VERSION 5.7 ;
  NOWIREEXTENSIONATPIN ON ;
  DIVIDERCHAR "/" ;
  BUSBITCHARS "[]" ;
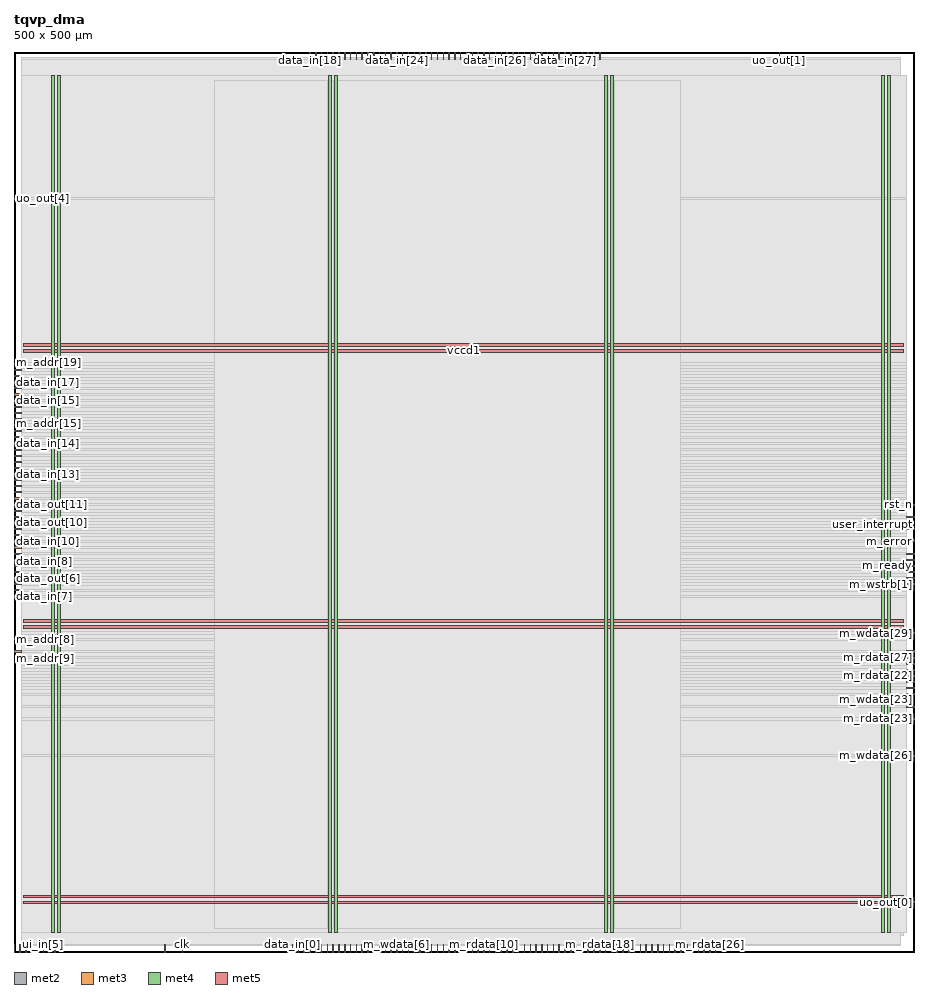
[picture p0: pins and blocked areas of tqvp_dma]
MACRO tqvp_dma
  CLASS BLOCK ;
  FOREIGN tqvp_dma ;
  ORIGIN 0.000 0.000 ;
  SIZE 500.000 BY 500.000 ;
  PIN address[0]
    DIRECTION INPUT ;
    USE SIGNAL ;
    ANTENNAGATEAREA 0.159000 ;
    PORT
      LAYER met2 ;
        RECT 248.030 496.000 248.310 500.000 ;
    END
  END address[0]
  PIN address[1]
    DIRECTION INPUT ;
    USE SIGNAL ;
    ANTENNAGATEAREA 0.159000 ;
    PORT
      LAYER met2 ;
        RECT 309.210 496.000 309.490 500.000 ;
    END
  END address[1]
  PIN address[2]
    DIRECTION INPUT ;
    USE SIGNAL ;
    ANTENNAGATEAREA 0.213000 ;
    PORT
      LAYER met2 ;
        RECT 251.250 496.000 251.530 500.000 ;
    END
  END address[2]
  PIN address[3]
    DIRECTION INPUT ;
    USE SIGNAL ;
    ANTENNAGATEAREA 0.213000 ;
    PORT
      LAYER met2 ;
        RECT 254.470 496.000 254.750 500.000 ;
    END
  END address[3]
  PIN address[4]
    DIRECTION INPUT ;
    USE SIGNAL ;
    ANTENNAGATEAREA 0.213000 ;
    PORT
      LAYER met2 ;
        RECT 257.690 496.000 257.970 500.000 ;
    END
  END address[4]
  PIN address[5]
    DIRECTION INPUT ;
    USE SIGNAL ;
    ANTENNAGATEAREA 0.159000 ;
    PORT
      LAYER met2 ;
        RECT 289.890 496.000 290.170 500.000 ;
    END
  END address[5]
  PIN clk
    DIRECTION INPUT ;
    USE SIGNAL ;
    ANTENNAGATEAREA 0.852000 ;
    ANTENNADIFFAREA 0.434700 ;
    PORT
      LAYER met2 ;
        RECT 93.470 0.000 93.750 4.000 ;
    END
  END clk
  PIN data_in[0]
    DIRECTION INPUT ;
    USE SIGNAL ;
    ANTENNAGATEAREA 0.213000 ;
    PORT
      LAYER met2 ;
        RECT 154.650 0.000 154.930 4.000 ;
    END
  END data_in[0]
  PIN data_in[10]
    DIRECTION INPUT ;
    USE SIGNAL ;
    ANTENNAGATEAREA 0.159000 ;
    PORT
      LAYER met3 ;
        RECT 0.000 227.840 4.000 228.440 ;
    END
  END data_in[10]
  PIN data_in[11]
    DIRECTION INPUT ;
    USE SIGNAL ;
    ANTENNAGATEAREA 0.159000 ;
    PORT
      LAYER met3 ;
        RECT 0.000 234.640 4.000 235.240 ;
    END
  END data_in[11]
  PIN data_in[12]
    DIRECTION INPUT ;
    USE SIGNAL ;
    ANTENNAGATEAREA 0.159000 ;
    PORT
      LAYER met3 ;
        RECT 0.000 261.840 4.000 262.440 ;
    END
  END data_in[12]
  PIN data_in[13]
    DIRECTION INPUT ;
    USE SIGNAL ;
    ANTENNAGATEAREA 0.159000 ;
    PORT
      LAYER met3 ;
        RECT 0.000 265.240 4.000 265.840 ;
    END
  END data_in[13]
  PIN data_in[14]
    DIRECTION INPUT ;
    USE SIGNAL ;
    ANTENNAGATEAREA 0.159000 ;
    PORT
      LAYER met3 ;
        RECT 0.000 282.240 4.000 282.840 ;
    END
  END data_in[14]
  PIN data_in[15]
    DIRECTION INPUT ;
    USE SIGNAL ;
    ANTENNAGATEAREA 0.159000 ;
    PORT
      LAYER met3 ;
        RECT 0.000 306.040 4.000 306.640 ;
    END
  END data_in[15]
  PIN data_in[16]
    DIRECTION INPUT ;
    USE SIGNAL ;
    ANTENNAGATEAREA 0.159000 ;
    PORT
      LAYER met3 ;
        RECT 0.000 319.640 4.000 320.240 ;
    END
  END data_in[16]
  PIN data_in[17]
    DIRECTION INPUT ;
    USE SIGNAL ;
    ANTENNAGATEAREA 0.159000 ;
    PORT
      LAYER met3 ;
        RECT 0.000 316.240 4.000 316.840 ;
    END
  END data_in[17]
  PIN data_in[18]
    DIRECTION INPUT ;
    USE SIGNAL ;
    ANTENNAGATEAREA 0.159000 ;
    PORT
      LAYER met2 ;
        RECT 164.310 496.000 164.590 500.000 ;
    END
  END data_in[18]
  PIN data_in[19]
    DIRECTION INPUT ;
    USE SIGNAL ;
    ANTENNAGATEAREA 0.159000 ;
    PORT
      LAYER met2 ;
        RECT 167.530 496.000 167.810 500.000 ;
    END
  END data_in[19]
  PIN data_in[1]
    DIRECTION INPUT ;
    USE SIGNAL ;
    ANTENNAGATEAREA 0.213000 ;
    PORT
      LAYER met2 ;
        RECT 219.050 0.000 219.330 4.000 ;
    END
  END data_in[1]
  PIN data_in[20]
    DIRECTION INPUT ;
    USE SIGNAL ;
    ANTENNAGATEAREA 0.159000 ;
    PORT
      LAYER met2 ;
        RECT 173.970 496.000 174.250 500.000 ;
    END
  END data_in[20]
  PIN data_in[21]
    DIRECTION INPUT ;
    USE SIGNAL ;
    ANTENNAGATEAREA 0.213000 ;
    PORT
      LAYER met2 ;
        RECT 170.750 496.000 171.030 500.000 ;
    END
  END data_in[21]
  PIN data_in[22]
    DIRECTION INPUT ;
    USE SIGNAL ;
    ANTENNAGATEAREA 0.159000 ;
    PORT
      LAYER met2 ;
        RECT 196.510 496.000 196.790 500.000 ;
    END
  END data_in[22]
  PIN data_in[23]
    DIRECTION INPUT ;
    USE SIGNAL ;
    ANTENNAGATEAREA 0.213000 ;
    PORT
      LAYER met2 ;
        RECT 202.950 496.000 203.230 500.000 ;
    END
  END data_in[23]
  PIN data_in[24]
    DIRECTION INPUT ;
    USE SIGNAL ;
    ANTENNAGATEAREA 0.159000 ;
    PORT
      LAYER met2 ;
        RECT 212.610 496.000 212.890 500.000 ;
    END
  END data_in[24]
  PIN data_in[25]
    DIRECTION INPUT ;
    USE SIGNAL ;
    ANTENNAGATEAREA 0.213000 ;
    PORT
      LAYER met2 ;
        RECT 222.270 496.000 222.550 500.000 ;
    END
  END data_in[25]
  PIN data_in[26]
    DIRECTION INPUT ;
    USE SIGNAL ;
    ANTENNAGATEAREA 0.213000 ;
    PORT
      LAYER met2 ;
        RECT 267.350 496.000 267.630 500.000 ;
    END
  END data_in[26]
  PIN data_in[27]
    DIRECTION INPUT ;
    USE SIGNAL ;
    ANTENNAGATEAREA 0.159000 ;
    PORT
      LAYER met2 ;
        RECT 305.990 496.000 306.270 500.000 ;
    END
  END data_in[27]
  PIN data_in[28]
    DIRECTION INPUT ;
    USE SIGNAL ;
    ANTENNAGATEAREA 0.159000 ;
    PORT
      LAYER met2 ;
        RECT 302.770 496.000 303.050 500.000 ;
    END
  END data_in[28]
  PIN data_in[29]
    DIRECTION INPUT ;
    USE SIGNAL ;
    ANTENNAGATEAREA 0.159000 ;
    PORT
      LAYER met2 ;
        RECT 299.550 496.000 299.830 500.000 ;
    END
  END data_in[29]
  PIN data_in[2]
    DIRECTION INPUT ;
    USE SIGNAL ;
    ANTENNAGATEAREA 0.213000 ;
    PORT
      LAYER met2 ;
        RECT 183.630 0.000 183.910 4.000 ;
    END
  END data_in[2]
  PIN data_in[30]
    DIRECTION INPUT ;
    USE SIGNAL ;
    ANTENNAGATEAREA 0.159000 ;
    PORT
      LAYER met2 ;
        RECT 296.330 496.000 296.610 500.000 ;
    END
  END data_in[30]
  PIN data_in[31]
    DIRECTION INPUT ;
    USE SIGNAL ;
    ANTENNAGATEAREA 0.159000 ;
    PORT
      LAYER met2 ;
        RECT 293.110 496.000 293.390 500.000 ;
    END
  END data_in[31]
  PIN data_in[3]
    DIRECTION INPUT ;
    USE SIGNAL ;
    ANTENNAGATEAREA 0.159000 ;
    PORT
      LAYER met2 ;
        RECT 202.950 0.000 203.230 4.000 ;
    END
  END data_in[3]
  PIN data_in[4]
    DIRECTION INPUT ;
    USE SIGNAL ;
    ANTENNAGATEAREA 0.213000 ;
    PORT
      LAYER met2 ;
        RECT 193.290 0.000 193.570 4.000 ;
    END
  END data_in[4]
  PIN data_in[5]
    DIRECTION INPUT ;
    USE SIGNAL ;
    ANTENNAGATEAREA 0.213000 ;
    PORT
      LAYER met2 ;
        RECT 170.750 0.000 171.030 4.000 ;
    END
  END data_in[5]
  PIN data_in[6]
    DIRECTION INPUT ;
    USE SIGNAL ;
    ANTENNAGATEAREA 0.159000 ;
    PORT
      LAYER met3 ;
        RECT 0.000 200.640 4.000 201.240 ;
    END
  END data_in[6]
  PIN data_in[7]
    DIRECTION INPUT ;
    USE SIGNAL ;
    ANTENNAGATEAREA 0.159000 ;
    PORT
      LAYER met3 ;
        RECT 0.000 197.240 4.000 197.840 ;
    END
  END data_in[7]
  PIN data_in[8]
    DIRECTION INPUT ;
    USE SIGNAL ;
    ANTENNAGATEAREA 0.159000 ;
    PORT
      LAYER met3 ;
        RECT 0.000 221.040 4.000 221.640 ;
    END
  END data_in[8]
  PIN data_in[9]
    DIRECTION INPUT ;
    USE SIGNAL ;
    ANTENNAGATEAREA 0.159000 ;
    PORT
      LAYER met3 ;
        RECT 0.000 224.440 4.000 225.040 ;
    END
  END data_in[9]
  PIN data_out[0]
    DIRECTION OUTPUT ;
    USE SIGNAL ;
    ANTENNADIFFAREA 0.445500 ;
    PORT
      LAYER met3 ;
        RECT 496.000 234.640 500.000 235.240 ;
    END
  END data_out[0]
  PIN data_out[10]
    DIRECTION OUTPUT ;
    USE SIGNAL ;
    ANTENNADIFFAREA 0.445500 ;
    PORT
      LAYER met3 ;
        RECT 0.000 238.040 4.000 238.640 ;
    END
  END data_out[10]
  PIN data_out[11]
    DIRECTION OUTPUT ;
    USE SIGNAL ;
    ANTENNADIFFAREA 0.445500 ;
    PORT
      LAYER met3 ;
        RECT 0.000 248.240 4.000 248.840 ;
    END
  END data_out[11]
  PIN data_out[12]
    DIRECTION OUTPUT ;
    USE SIGNAL ;
    ANTENNADIFFAREA 0.445500 ;
    PORT
      LAYER met3 ;
        RECT 0.000 255.040 4.000 255.640 ;
    END
  END data_out[12]
  PIN data_out[13]
    DIRECTION OUTPUT ;
    USE SIGNAL ;
    ANTENNADIFFAREA 0.445500 ;
    PORT
      LAYER met3 ;
        RECT 0.000 272.040 4.000 272.640 ;
    END
  END data_out[13]
  PIN data_out[14]
    DIRECTION OUTPUT ;
    USE SIGNAL ;
    ANTENNADIFFAREA 0.445500 ;
    PORT
      LAYER met3 ;
        RECT 0.000 275.440 4.000 276.040 ;
    END
  END data_out[14]
  PIN data_out[15]
    DIRECTION OUTPUT ;
    USE SIGNAL ;
    ANTENNADIFFAREA 0.445500 ;
    PORT
      LAYER met3 ;
        RECT 0.000 285.640 4.000 286.240 ;
    END
  END data_out[15]
  PIN data_out[16]
    DIRECTION OUTPUT ;
    USE SIGNAL ;
    ANTENNADIFFAREA 0.445500 ;
    PORT
      LAYER met3 ;
        RECT 0.000 292.440 4.000 293.040 ;
    END
  END data_out[16]
  PIN data_out[17]
    DIRECTION OUTPUT ;
    USE SIGNAL ;
    ANTENNADIFFAREA 0.445500 ;
    PORT
      LAYER met3 ;
        RECT 0.000 302.640 4.000 303.240 ;
    END
  END data_out[17]
  PIN data_out[18]
    DIRECTION OUTPUT ;
    USE SIGNAL ;
    ANTENNADIFFAREA 0.445500 ;
    PORT
      LAYER met3 ;
        RECT 0.000 312.840 4.000 313.440 ;
    END
  END data_out[18]
  PIN data_out[19]
    DIRECTION OUTPUT ;
    USE SIGNAL ;
    ANTENNADIFFAREA 0.445500 ;
    PORT
      LAYER met3 ;
        RECT 0.000 309.440 4.000 310.040 ;
    END
  END data_out[19]
  PIN data_out[1]
    DIRECTION OUTPUT ;
    USE SIGNAL ;
    ANTENNADIFFAREA 0.445500 ;
    PORT
      LAYER met2 ;
        RECT 167.530 0.000 167.810 4.000 ;
    END
  END data_out[1]
  PIN data_out[20]
    DIRECTION OUTPUT ;
    USE SIGNAL ;
    ANTENNADIFFAREA 0.795200 ;
    PORT
      LAYER met2 ;
        RECT 190.070 496.000 190.350 500.000 ;
    END
  END data_out[20]
  PIN data_out[21]
    DIRECTION OUTPUT ;
    USE SIGNAL ;
    ANTENNADIFFAREA 0.795200 ;
    PORT
      LAYER met2 ;
        RECT 193.290 496.000 193.570 500.000 ;
    END
  END data_out[21]
  PIN data_out[22]
    DIRECTION OUTPUT ;
    USE SIGNAL ;
    ANTENNADIFFAREA 0.795200 ;
    PORT
      LAYER met2 ;
        RECT 215.830 496.000 216.110 500.000 ;
    END
  END data_out[22]
  PIN data_out[23]
    DIRECTION OUTPUT ;
    USE SIGNAL ;
    ANTENNADIFFAREA 0.795200 ;
    PORT
      LAYER met2 ;
        RECT 219.050 496.000 219.330 500.000 ;
    END
  END data_out[23]
  PIN data_out[24]
    DIRECTION OUTPUT ;
    USE SIGNAL ;
    ANTENNADIFFAREA 0.795200 ;
    PORT
      LAYER met2 ;
        RECT 225.490 496.000 225.770 500.000 ;
    END
  END data_out[24]
  PIN data_out[25]
    DIRECTION OUTPUT ;
    USE SIGNAL ;
    ANTENNADIFFAREA 0.795200 ;
    PORT
      LAYER met2 ;
        RECT 209.390 496.000 209.670 500.000 ;
    END
  END data_out[25]
  PIN data_out[26]
    DIRECTION OUTPUT ;
    USE SIGNAL ;
    ANTENNADIFFAREA 0.795200 ;
    PORT
      LAYER met2 ;
        RECT 270.570 496.000 270.850 500.000 ;
    END
  END data_out[26]
  PIN data_out[27]
    DIRECTION OUTPUT ;
    USE SIGNAL ;
    ANTENNADIFFAREA 0.795200 ;
    PORT
      LAYER met2 ;
        RECT 273.790 496.000 274.070 500.000 ;
    END
  END data_out[27]
  PIN data_out[28]
    DIRECTION OUTPUT ;
    USE SIGNAL ;
    ANTENNADIFFAREA 0.795200 ;
    PORT
      LAYER met2 ;
        RECT 280.230 496.000 280.510 500.000 ;
    END
  END data_out[28]
  PIN data_out[29]
    DIRECTION OUTPUT ;
    USE SIGNAL ;
    ANTENNADIFFAREA 0.795200 ;
    PORT
      LAYER met2 ;
        RECT 260.910 496.000 261.190 500.000 ;
    END
  END data_out[29]
  PIN data_out[2]
    DIRECTION OUTPUT ;
    USE SIGNAL ;
    ANTENNADIFFAREA 0.445500 ;
    PORT
      LAYER met2 ;
        RECT 251.250 0.000 251.530 4.000 ;
    END
  END data_out[2]
  PIN data_out[30]
    DIRECTION OUTPUT ;
    USE SIGNAL ;
    ANTENNADIFFAREA 0.795200 ;
    PORT
      LAYER met2 ;
        RECT 286.670 496.000 286.950 500.000 ;
    END
  END data_out[30]
  PIN data_out[31]
    DIRECTION OUTPUT ;
    USE SIGNAL ;
    ANTENNADIFFAREA 0.795200 ;
    PORT
      LAYER met2 ;
        RECT 264.130 496.000 264.410 500.000 ;
    END
  END data_out[31]
  PIN data_out[3]
    DIRECTION OUTPUT ;
    USE SIGNAL ;
    ANTENNADIFFAREA 0.445500 ;
    PORT
      LAYER met2 ;
        RECT 186.850 0.000 187.130 4.000 ;
    END
  END data_out[3]
  PIN data_out[4]
    DIRECTION OUTPUT ;
    USE SIGNAL ;
    ANTENNADIFFAREA 0.445500 ;
    PORT
      LAYER met2 ;
        RECT 248.030 0.000 248.310 4.000 ;
    END
  END data_out[4]
  PIN data_out[5]
    DIRECTION OUTPUT ;
    USE SIGNAL ;
    ANTENNADIFFAREA 0.445500 ;
    PORT
      LAYER met3 ;
        RECT 0.000 214.240 4.000 214.840 ;
    END
  END data_out[5]
  PIN data_out[6]
    DIRECTION OUTPUT ;
    USE SIGNAL ;
    ANTENNADIFFAREA 0.445500 ;
    PORT
      LAYER met3 ;
        RECT 0.000 207.440 4.000 208.040 ;
    END
  END data_out[6]
  PIN data_out[7]
    DIRECTION OUTPUT ;
    USE SIGNAL ;
    ANTENNADIFFAREA 0.445500 ;
    PORT
      LAYER met3 ;
        RECT 0.000 210.840 4.000 211.440 ;
    END
  END data_out[7]
  PIN data_out[8]
    DIRECTION OUTPUT ;
    USE SIGNAL ;
    ANTENNADIFFAREA 0.445500 ;
    PORT
      LAYER met3 ;
        RECT 0.000 217.640 4.000 218.240 ;
    END
  END data_out[8]
  PIN data_out[9]
    DIRECTION OUTPUT ;
    USE SIGNAL ;
    ANTENNADIFFAREA 0.445500 ;
    PORT
      LAYER met3 ;
        RECT 0.000 231.240 4.000 231.840 ;
    END
  END data_out[9]
  PIN data_read_n[0]
    DIRECTION INPUT ;
    USE SIGNAL ;
    ANTENNAGATEAREA 0.213000 ;
    PORT
      LAYER met2 ;
        RECT 244.810 496.000 245.090 500.000 ;
    END
  END data_read_n[0]
  PIN data_read_n[1]
    DIRECTION INPUT ;
    USE SIGNAL ;
    ANTENNAGATEAREA 0.213000 ;
    PORT
      LAYER met2 ;
        RECT 241.590 496.000 241.870 500.000 ;
    END
  END data_read_n[1]
  PIN data_ready
    DIRECTION OUTPUT ;
    USE SIGNAL ;
    ANTENNADIFFAREA 0.445500 ;
    PORT
      LAYER met3 ;
        RECT 0.000 204.040 4.000 204.640 ;
    END
  END data_ready
  PIN data_write_n[0]
    DIRECTION INPUT ;
    USE SIGNAL ;
    ANTENNAGATEAREA 0.159000 ;
    PORT
      LAYER met2 ;
        RECT 231.930 496.000 232.210 500.000 ;
    END
  END data_write_n[0]
  PIN data_write_n[1]
    DIRECTION INPUT ;
    USE SIGNAL ;
    ANTENNAGATEAREA 0.159000 ;
    PORT
      LAYER met2 ;
        RECT 238.370 496.000 238.650 500.000 ;
    END
  END data_write_n[1]
  PIN idle
    DIRECTION OUTPUT ;
    USE SIGNAL ;
    ANTENNADIFFAREA 0.795200 ;
    PORT
      LAYER met2 ;
        RECT 186.850 496.000 187.130 500.000 ;
    END
  END idle
  PIN m_addr[0]
    DIRECTION OUTPUT ;
    USE SIGNAL ;
    ANTENNADIFFAREA 0.445500 ;
    PORT
      LAYER met2 ;
        RECT 157.870 0.000 158.150 4.000 ;
    END
  END m_addr[0]
  PIN m_addr[10]
    DIRECTION OUTPUT ;
    USE SIGNAL ;
    ANTENNADIFFAREA 0.445500 ;
    PORT
      LAYER met3 ;
        RECT 0.000 244.840 4.000 245.440 ;
    END
  END m_addr[10]
  PIN m_addr[11]
    DIRECTION OUTPUT ;
    USE SIGNAL ;
    ANTENNADIFFAREA 0.445500 ;
    PORT
      LAYER met3 ;
        RECT 0.000 251.640 4.000 252.240 ;
    END
  END m_addr[11]
  PIN m_addr[12]
    DIRECTION OUTPUT ;
    USE SIGNAL ;
    ANTENNADIFFAREA 0.445500 ;
    PORT
      LAYER met3 ;
        RECT 0.000 258.440 4.000 259.040 ;
    END
  END m_addr[12]
  PIN m_addr[13]
    DIRECTION OUTPUT ;
    USE SIGNAL ;
    ANTENNADIFFAREA 0.445500 ;
    PORT
      LAYER met3 ;
        RECT 0.000 268.640 4.000 269.240 ;
    END
  END m_addr[13]
  PIN m_addr[14]
    DIRECTION OUTPUT ;
    USE SIGNAL ;
    ANTENNADIFFAREA 0.445500 ;
    PORT
      LAYER met3 ;
        RECT 0.000 278.840 4.000 279.440 ;
    END
  END m_addr[14]
  PIN m_addr[15]
    DIRECTION OUTPUT ;
    USE SIGNAL ;
    ANTENNADIFFAREA 0.445500 ;
    PORT
      LAYER met3 ;
        RECT 0.000 289.040 4.000 289.640 ;
    END
  END m_addr[15]
  PIN m_addr[16]
    DIRECTION OUTPUT ;
    USE SIGNAL ;
    ANTENNADIFFAREA 0.445500 ;
    PORT
      LAYER met3 ;
        RECT 0.000 295.840 4.000 296.440 ;
    END
  END m_addr[16]
  PIN m_addr[17]
    DIRECTION OUTPUT ;
    USE SIGNAL ;
    ANTENNADIFFAREA 0.445500 ;
    PORT
      LAYER met3 ;
        RECT 0.000 299.240 4.000 299.840 ;
    END
  END m_addr[17]
  PIN m_addr[18]
    DIRECTION OUTPUT ;
    USE SIGNAL ;
    ANTENNADIFFAREA 0.445500 ;
    PORT
      LAYER met3 ;
        RECT 0.000 326.440 4.000 327.040 ;
    END
  END m_addr[18]
  PIN m_addr[19]
    DIRECTION OUTPUT ;
    USE SIGNAL ;
    ANTENNADIFFAREA 0.445500 ;
    PORT
      LAYER met3 ;
        RECT 0.000 323.040 4.000 323.640 ;
    END
  END m_addr[19]
  PIN m_addr[1]
    DIRECTION OUTPUT ;
    USE SIGNAL ;
    ANTENNADIFFAREA 0.445500 ;
    PORT
      LAYER met2 ;
        RECT 254.470 0.000 254.750 4.000 ;
    END
  END m_addr[1]
  PIN m_addr[20]
    DIRECTION OUTPUT ;
    USE SIGNAL ;
    ANTENNADIFFAREA 0.795200 ;
    PORT
      LAYER met2 ;
        RECT 177.190 496.000 177.470 500.000 ;
    END
  END m_addr[20]
  PIN m_addr[21]
    DIRECTION OUTPUT ;
    USE SIGNAL ;
    ANTENNADIFFAREA 0.795200 ;
    PORT
      LAYER met2 ;
        RECT 180.410 496.000 180.690 500.000 ;
    END
  END m_addr[21]
  PIN m_addr[22]
    DIRECTION OUTPUT ;
    USE SIGNAL ;
    ANTENNADIFFAREA 0.795200 ;
    PORT
      LAYER met2 ;
        RECT 199.730 496.000 200.010 500.000 ;
    END
  END m_addr[22]
  PIN m_addr[23]
    DIRECTION OUTPUT ;
    USE SIGNAL ;
    ANTENNADIFFAREA 0.795200 ;
    PORT
      LAYER met2 ;
        RECT 206.170 496.000 206.450 500.000 ;
    END
  END m_addr[23]
  PIN m_addr[24]
    DIRECTION OUTPUT ;
    USE SIGNAL ;
    ANTENNADIFFAREA 0.795200 ;
    PORT
      LAYER met2 ;
        RECT 228.710 496.000 228.990 500.000 ;
    END
  END m_addr[24]
  PIN m_addr[25]
    DIRECTION OUTPUT ;
    USE SIGNAL ;
    ANTENNADIFFAREA 0.795200 ;
    PORT
      LAYER met2 ;
        RECT 235.150 496.000 235.430 500.000 ;
    END
  END m_addr[25]
  PIN m_addr[26]
    DIRECTION OUTPUT ;
    USE SIGNAL ;
    ANTENNADIFFAREA 0.795200 ;
    PORT
      LAYER met2 ;
        RECT 277.010 496.000 277.290 500.000 ;
    END
  END m_addr[26]
  PIN m_addr[27]
    DIRECTION OUTPUT ;
    USE SIGNAL ;
    ANTENNADIFFAREA 0.795200 ;
    PORT
      LAYER met2 ;
        RECT 283.450 496.000 283.730 500.000 ;
    END
  END m_addr[27]
  PIN m_addr[28]
    DIRECTION OUTPUT ;
    USE SIGNAL ;
    ANTENNADIFFAREA 0.795200 ;
    PORT
      LAYER met2 ;
        RECT 325.310 496.000 325.590 500.000 ;
    END
  END m_addr[28]
  PIN m_addr[29]
    DIRECTION OUTPUT ;
    USE SIGNAL ;
    ANTENNADIFFAREA 0.795200 ;
    PORT
      LAYER met2 ;
        RECT 322.090 496.000 322.370 500.000 ;
    END
  END m_addr[29]
  PIN m_addr[2]
    DIRECTION OUTPUT ;
    USE SIGNAL ;
    ANTENNADIFFAREA 0.445500 ;
    PORT
      LAYER met2 ;
        RECT 244.810 0.000 245.090 4.000 ;
    END
  END m_addr[2]
  PIN m_addr[30]
    DIRECTION OUTPUT ;
    USE SIGNAL ;
    ANTENNADIFFAREA 0.795200 ;
    PORT
      LAYER met2 ;
        RECT 318.870 496.000 319.150 500.000 ;
    END
  END m_addr[30]
  PIN m_addr[31]
    DIRECTION OUTPUT ;
    USE SIGNAL ;
    ANTENNADIFFAREA 0.795200 ;
    PORT
      LAYER met2 ;
        RECT 315.650 496.000 315.930 500.000 ;
    END
  END m_addr[31]
  PIN m_addr[3]
    DIRECTION OUTPUT ;
    USE SIGNAL ;
    ANTENNADIFFAREA 0.445500 ;
    PORT
      LAYER met2 ;
        RECT 225.490 0.000 225.770 4.000 ;
    END
  END m_addr[3]
  PIN m_addr[4]
    DIRECTION OUTPUT ;
    USE SIGNAL ;
    ANTENNADIFFAREA 0.445500 ;
    PORT
      LAYER met2 ;
        RECT 235.150 0.000 235.430 4.000 ;
    END
  END m_addr[4]
  PIN m_addr[5]
    DIRECTION OUTPUT ;
    USE SIGNAL ;
    ANTENNADIFFAREA 0.445500 ;
    PORT
      LAYER met2 ;
        RECT 190.070 0.000 190.350 4.000 ;
    END
  END m_addr[5]
  PIN m_addr[6]
    DIRECTION OUTPUT ;
    USE SIGNAL ;
    ANTENNADIFFAREA 0.445500 ;
    PORT
      LAYER met2 ;
        RECT 177.190 0.000 177.470 4.000 ;
    END
  END m_addr[6]
  PIN m_addr[7]
    DIRECTION OUTPUT ;
    USE SIGNAL ;
    ANTENNADIFFAREA 0.445500 ;
    PORT
      LAYER met2 ;
        RECT 173.970 0.000 174.250 4.000 ;
    END
  END m_addr[7]
  PIN m_addr[8]
    DIRECTION OUTPUT ;
    USE SIGNAL ;
    ANTENNADIFFAREA 0.445500 ;
    PORT
      LAYER met3 ;
        RECT 0.000 173.440 4.000 174.040 ;
    END
  END m_addr[8]
  PIN m_addr[9]
    DIRECTION OUTPUT ;
    USE SIGNAL ;
    ANTENNADIFFAREA 0.445500 ;
    PORT
      LAYER met3 ;
        RECT 0.000 166.640 4.000 167.240 ;
    END
  END m_addr[9]
  PIN m_error
    DIRECTION INPUT ;
    USE SIGNAL ;
    ANTENNAGATEAREA 0.159000 ;
    PORT
      LAYER met3 ;
        RECT 496.000 227.840 500.000 228.440 ;
    END
  END m_error
  PIN m_rdata[0]
    DIRECTION INPUT ;
    USE SIGNAL ;
    ANTENNAGATEAREA 0.213000 ;
    PORT
      LAYER met2 ;
        RECT 196.510 0.000 196.790 4.000 ;
    END
  END m_rdata[0]
  PIN m_rdata[10]
    DIRECTION INPUT ;
    USE SIGNAL ;
    ANTENNAGATEAREA 0.196500 ;
    PORT
      LAYER met2 ;
        RECT 260.910 0.000 261.190 4.000 ;
    END
  END m_rdata[10]
  PIN m_rdata[11]
    DIRECTION INPUT ;
    USE SIGNAL ;
    ANTENNAGATEAREA 0.196500 ;
    PORT
      LAYER met2 ;
        RECT 267.350 0.000 267.630 4.000 ;
    END
  END m_rdata[11]
  PIN m_rdata[12]
    DIRECTION INPUT ;
    USE SIGNAL ;
    ANTENNAGATEAREA 0.213000 ;
    PORT
      LAYER met2 ;
        RECT 389.710 0.000 389.990 4.000 ;
    END
  END m_rdata[12]
  PIN m_rdata[13]
    DIRECTION INPUT ;
    USE SIGNAL ;
    ANTENNAGATEAREA 0.213000 ;
    PORT
      LAYER met2 ;
        RECT 161.090 0.000 161.370 4.000 ;
    END
  END m_rdata[13]
  PIN m_rdata[14]
    DIRECTION INPUT ;
    USE SIGNAL ;
    ANTENNAGATEAREA 0.196500 ;
    PORT
      LAYER met2 ;
        RECT 296.330 0.000 296.610 4.000 ;
    END
  END m_rdata[14]
  PIN m_rdata[15]
    DIRECTION INPUT ;
    USE SIGNAL ;
    ANTENNAGATEAREA 0.213000 ;
    PORT
      LAYER met2 ;
        RECT 383.270 0.000 383.550 4.000 ;
    END
  END m_rdata[15]
  PIN m_rdata[16]
    DIRECTION INPUT ;
    USE SIGNAL ;
    ANTENNAGATEAREA 0.126000 ;
    PORT
      LAYER met2 ;
        RECT 376.830 0.000 377.110 4.000 ;
    END
  END m_rdata[16]
  PIN m_rdata[17]
    DIRECTION INPUT ;
    USE SIGNAL ;
    ANTENNAGATEAREA 0.126000 ;
    PORT
      LAYER met2 ;
        RECT 370.390 0.000 370.670 4.000 ;
    END
  END m_rdata[17]
  PIN m_rdata[18]
    DIRECTION INPUT ;
    USE SIGNAL ;
    ANTENNAGATEAREA 0.126000 ;
    PORT
      LAYER met2 ;
        RECT 325.310 0.000 325.590 4.000 ;
    END
  END m_rdata[18]
  PIN m_rdata[19]
    DIRECTION INPUT ;
    USE SIGNAL ;
    ANTENNAGATEAREA 0.196500 ;
    PORT
      LAYER met2 ;
        RECT 328.530 0.000 328.810 4.000 ;
    END
  END m_rdata[19]
  PIN m_rdata[1]
    DIRECTION INPUT ;
    USE SIGNAL ;
    ANTENNAGATEAREA 0.213000 ;
    PORT
      LAYER met2 ;
        RECT 199.730 0.000 200.010 4.000 ;
    END
  END m_rdata[1]
  PIN m_rdata[20]
    DIRECTION INPUT ;
    USE SIGNAL ;
    ANTENNAGATEAREA 0.126000 ;
    PORT
      LAYER met3 ;
        RECT 496.000 166.640 500.000 167.240 ;
    END
  END m_rdata[20]
  PIN m_rdata[21]
    DIRECTION INPUT ;
    USE SIGNAL ;
    ANTENNAGATEAREA 0.126000 ;
    PORT
      LAYER met2 ;
        RECT 360.730 0.000 361.010 4.000 ;
    END
  END m_rdata[21]
  PIN m_rdata[22]
    DIRECTION INPUT ;
    USE SIGNAL ;
    ANTENNAGATEAREA 0.126000 ;
    PORT
      LAYER met3 ;
        RECT 496.000 153.040 500.000 153.640 ;
    END
  END m_rdata[22]
  PIN m_rdata[23]
    DIRECTION INPUT ;
    USE SIGNAL ;
    ANTENNAGATEAREA 0.126000 ;
    ANTENNADIFFAREA 0.434700 ;
    PORT
      LAYER met3 ;
        RECT 496.000 129.240 500.000 129.840 ;
    END
  END m_rdata[23]
  PIN m_rdata[24]
    DIRECTION INPUT ;
    USE SIGNAL ;
    ANTENNAGATEAREA 0.213000 ;
    PORT
      LAYER met2 ;
        RECT 357.510 0.000 357.790 4.000 ;
    END
  END m_rdata[24]
  PIN m_rdata[25]
    DIRECTION INPUT ;
    USE SIGNAL ;
    ANTENNAGATEAREA 0.126000 ;
    PORT
      LAYER met2 ;
        RECT 363.950 0.000 364.230 4.000 ;
    END
  END m_rdata[25]
  PIN m_rdata[26]
    DIRECTION INPUT ;
    USE SIGNAL ;
    ANTENNAGATEAREA 0.126000 ;
    PORT
      LAYER met2 ;
        RECT 386.490 0.000 386.770 4.000 ;
    END
  END m_rdata[26]
  PIN m_rdata[27]
    DIRECTION INPUT ;
    USE SIGNAL ;
    ANTENNAGATEAREA 0.213000 ;
    PORT
      LAYER met3 ;
        RECT 496.000 163.240 500.000 163.840 ;
    END
  END m_rdata[27]
  PIN m_rdata[28]
    DIRECTION INPUT ;
    USE SIGNAL ;
    ANTENNAGATEAREA 0.213000 ;
    PORT
      LAYER met2 ;
        RECT 334.970 0.000 335.250 4.000 ;
    END
  END m_rdata[28]
  PIN m_rdata[29]
    DIRECTION INPUT ;
    USE SIGNAL ;
    ANTENNAGATEAREA 0.213000 ;
    PORT
      LAYER met2 ;
        RECT 354.290 0.000 354.570 4.000 ;
    END
  END m_rdata[29]
  PIN m_rdata[2]
    DIRECTION INPUT ;
    USE SIGNAL ;
    ANTENNAGATEAREA 0.213000 ;
    PORT
      LAYER met2 ;
        RECT 231.930 0.000 232.210 4.000 ;
    END
  END m_rdata[2]
  PIN m_rdata[30]
    DIRECTION INPUT ;
    USE SIGNAL ;
    ANTENNAGATEAREA 0.213000 ;
    PORT
      LAYER met2 ;
        RECT 322.090 0.000 322.370 4.000 ;
    END
  END m_rdata[30]
  PIN m_rdata[31]
    DIRECTION INPUT ;
    USE SIGNAL ;
    ANTENNAGATEAREA 0.213000 ;
    PORT
      LAYER met2 ;
        RECT 312.430 0.000 312.710 4.000 ;
    END
  END m_rdata[31]
  PIN m_rdata[3]
    DIRECTION INPUT ;
    USE SIGNAL ;
    ANTENNAGATEAREA 0.213000 ;
    PORT
      LAYER met2 ;
        RECT 228.710 0.000 228.990 4.000 ;
    END
  END m_rdata[3]
  PIN m_rdata[4]
    DIRECTION INPUT ;
    USE SIGNAL ;
    ANTENNAGATEAREA 0.213000 ;
    PORT
      LAYER met2 ;
        RECT 209.390 0.000 209.670 4.000 ;
    END
  END m_rdata[4]
  PIN m_rdata[5]
    DIRECTION INPUT ;
    USE SIGNAL ;
    ANTENNAGATEAREA 0.213000 ;
    PORT
      LAYER met2 ;
        RECT 270.570 0.000 270.850 4.000 ;
    END
  END m_rdata[5]
  PIN m_rdata[6]
    DIRECTION INPUT ;
    USE SIGNAL ;
    ANTENNAGATEAREA 0.126000 ;
    PORT
      LAYER met2 ;
        RECT 206.170 0.000 206.450 4.000 ;
    END
  END m_rdata[6]
  PIN m_rdata[7]
    DIRECTION INPUT ;
    USE SIGNAL ;
    ANTENNAGATEAREA 0.213000 ;
    PORT
      LAYER met2 ;
        RECT 164.310 0.000 164.590 4.000 ;
    END
  END m_rdata[7]
  PIN m_rdata[8]
    DIRECTION INPUT ;
    USE SIGNAL ;
    ANTENNAGATEAREA 0.213000 ;
    PORT
      LAYER met2 ;
        RECT 309.210 0.000 309.490 4.000 ;
    END
  END m_rdata[8]
  PIN m_rdata[9]
    DIRECTION INPUT ;
    USE SIGNAL ;
    ANTENNAGATEAREA 0.126000 ;
    PORT
      LAYER met2 ;
        RECT 264.130 0.000 264.410 4.000 ;
    END
  END m_rdata[9]
  PIN m_read
    DIRECTION OUTPUT ;
    USE SIGNAL ;
    ANTENNADIFFAREA 0.445500 ;
    PORT
      LAYER met3 ;
        RECT 496.000 217.640 500.000 218.240 ;
    END
  END m_read
  PIN m_ready
    DIRECTION INPUT ;
    USE SIGNAL ;
    ANTENNAGATEAREA 0.213000 ;
    PORT
      LAYER met3 ;
        RECT 496.000 214.240 500.000 214.840 ;
    END
  END m_ready
  PIN m_valid
    DIRECTION OUTPUT ;
    USE SIGNAL ;
    ANTENNADIFFAREA 0.445500 ;
    PORT
      LAYER met3 ;
        RECT 496.000 221.040 500.000 221.640 ;
    END
  END m_valid
  PIN m_wdata[0]
    DIRECTION OUTPUT ;
    USE SIGNAL ;
    ANTENNADIFFAREA 0.445500 ;
    PORT
      LAYER met2 ;
        RECT 222.270 0.000 222.550 4.000 ;
    END
  END m_wdata[0]
  PIN m_wdata[10]
    DIRECTION OUTPUT ;
    USE SIGNAL ;
    ANTENNADIFFAREA 0.445500 ;
    PORT
      LAYER met2 ;
        RECT 280.230 0.000 280.510 4.000 ;
    END
  END m_wdata[10]
  PIN m_wdata[11]
    DIRECTION OUTPUT ;
    USE SIGNAL ;
    ANTENNADIFFAREA 0.445500 ;
    PORT
      LAYER met2 ;
        RECT 283.450 0.000 283.730 4.000 ;
    END
  END m_wdata[11]
  PIN m_wdata[12]
    DIRECTION OUTPUT ;
    USE SIGNAL ;
    ANTENNADIFFAREA 0.445500 ;
    PORT
      LAYER met2 ;
        RECT 315.650 0.000 315.930 4.000 ;
    END
  END m_wdata[12]
  PIN m_wdata[13]
    DIRECTION OUTPUT ;
    USE SIGNAL ;
    ANTENNADIFFAREA 0.445500 ;
    PORT
      LAYER met2 ;
        RECT 286.670 0.000 286.950 4.000 ;
    END
  END m_wdata[13]
  PIN m_wdata[14]
    DIRECTION OUTPUT ;
    USE SIGNAL ;
    ANTENNADIFFAREA 0.445500 ;
    PORT
      LAYER met2 ;
        RECT 331.750 0.000 332.030 4.000 ;
    END
  END m_wdata[14]
  PIN m_wdata[15]
    DIRECTION OUTPUT ;
    USE SIGNAL ;
    ANTENNADIFFAREA 0.445500 ;
    PORT
      LAYER met2 ;
        RECT 305.990 0.000 306.270 4.000 ;
    END
  END m_wdata[15]
  PIN m_wdata[16]
    DIRECTION OUTPUT ;
    USE SIGNAL ;
    ANTENNADIFFAREA 0.445500 ;
    PORT
      LAYER met2 ;
        RECT 380.050 0.000 380.330 4.000 ;
    END
  END m_wdata[16]
  PIN m_wdata[17]
    DIRECTION OUTPUT ;
    USE SIGNAL ;
    ANTENNADIFFAREA 0.445500 ;
    PORT
      LAYER met2 ;
        RECT 347.850 0.000 348.130 4.000 ;
    END
  END m_wdata[17]
  PIN m_wdata[18]
    DIRECTION OUTPUT ;
    USE SIGNAL ;
    ANTENNADIFFAREA 0.445500 ;
    PORT
      LAYER met2 ;
        RECT 338.190 0.000 338.470 4.000 ;
    END
  END m_wdata[18]
  PIN m_wdata[19]
    DIRECTION OUTPUT ;
    USE SIGNAL ;
    ANTENNADIFFAREA 0.445500 ;
    PORT
      LAYER met2 ;
        RECT 341.410 0.000 341.690 4.000 ;
    END
  END m_wdata[19]
  PIN m_wdata[1]
    DIRECTION OUTPUT ;
    USE SIGNAL ;
    ANTENNADIFFAREA 0.445500 ;
    PORT
      LAYER met2 ;
        RECT 215.830 0.000 216.110 4.000 ;
    END
  END m_wdata[1]
  PIN m_wdata[20]
    DIRECTION OUTPUT ;
    USE SIGNAL ;
    ANTENNADIFFAREA 0.445500 ;
    PORT
      LAYER met3 ;
        RECT 496.000 159.840 500.000 160.440 ;
    END
  END m_wdata[20]
  PIN m_wdata[21]
    DIRECTION OUTPUT ;
    USE SIGNAL ;
    ANTENNADIFFAREA 0.445500 ;
    PORT
      LAYER met2 ;
        RECT 351.070 0.000 351.350 4.000 ;
    END
  END m_wdata[21]
  PIN m_wdata[22]
    DIRECTION OUTPUT ;
    USE SIGNAL ;
    ANTENNADIFFAREA 0.445500 ;
    PORT
      LAYER met3 ;
        RECT 496.000 149.640 500.000 150.240 ;
    END
  END m_wdata[22]
  PIN m_wdata[23]
    DIRECTION OUTPUT ;
    USE SIGNAL ;
    ANTENNADIFFAREA 0.445500 ;
    PORT
      LAYER met3 ;
        RECT 496.000 136.040 500.000 136.640 ;
    END
  END m_wdata[23]
  PIN m_wdata[24]
    DIRECTION OUTPUT ;
    USE SIGNAL ;
    ANTENNADIFFAREA 0.445500 ;
    PORT
      LAYER met3 ;
        RECT 496.000 146.240 500.000 146.840 ;
    END
  END m_wdata[24]
  PIN m_wdata[25]
    DIRECTION OUTPUT ;
    USE SIGNAL ;
    ANTENNADIFFAREA 0.445500 ;
    PORT
      LAYER met2 ;
        RECT 373.610 0.000 373.890 4.000 ;
    END
  END m_wdata[25]
  PIN m_wdata[26]
    DIRECTION OUTPUT ;
    USE SIGNAL ;
    ANTENNADIFFAREA 0.445500 ;
    PORT
      LAYER met3 ;
        RECT 496.000 108.840 500.000 109.440 ;
    END
  END m_wdata[26]
  PIN m_wdata[27]
    DIRECTION OUTPUT ;
    USE SIGNAL ;
    ANTENNADIFFAREA 0.445500 ;
    PORT
      LAYER met3 ;
        RECT 496.000 156.440 500.000 157.040 ;
    END
  END m_wdata[27]
  PIN m_wdata[28]
    DIRECTION OUTPUT ;
    USE SIGNAL ;
    ANTENNADIFFAREA 0.445500 ;
    PORT
      LAYER met2 ;
        RECT 344.630 0.000 344.910 4.000 ;
    END
  END m_wdata[28]
  PIN m_wdata[29]
    DIRECTION OUTPUT ;
    USE SIGNAL ;
    ANTENNADIFFAREA 0.445500 ;
    PORT
      LAYER met3 ;
        RECT 496.000 176.840 500.000 177.440 ;
    END
  END m_wdata[29]
  PIN m_wdata[2]
    DIRECTION OUTPUT ;
    USE SIGNAL ;
    ANTENNADIFFAREA 0.445500 ;
    PORT
      LAYER met2 ;
        RECT 257.690 0.000 257.970 4.000 ;
    END
  END m_wdata[2]
  PIN m_wdata[30]
    DIRECTION OUTPUT ;
    USE SIGNAL ;
    ANTENNADIFFAREA 0.445500 ;
    PORT
      LAYER met2 ;
        RECT 318.870 0.000 319.150 4.000 ;
    END
  END m_wdata[30]
  PIN m_wdata[31]
    DIRECTION OUTPUT ;
    USE SIGNAL ;
    ANTENNADIFFAREA 0.445500 ;
    PORT
      LAYER met2 ;
        RECT 302.770 0.000 303.050 4.000 ;
    END
  END m_wdata[31]
  PIN m_wdata[3]
    DIRECTION OUTPUT ;
    USE SIGNAL ;
    ANTENNADIFFAREA 0.445500 ;
    PORT
      LAYER met2 ;
        RECT 241.590 0.000 241.870 4.000 ;
    END
  END m_wdata[3]
  PIN m_wdata[4]
    DIRECTION OUTPUT ;
    USE SIGNAL ;
    ANTENNADIFFAREA 0.445500 ;
    PORT
      LAYER met2 ;
        RECT 180.410 0.000 180.690 4.000 ;
    END
  END m_wdata[4]
  PIN m_wdata[5]
    DIRECTION OUTPUT ;
    USE SIGNAL ;
    ANTENNADIFFAREA 0.445500 ;
    PORT
      LAYER met2 ;
        RECT 277.010 0.000 277.290 4.000 ;
    END
  END m_wdata[5]
  PIN m_wdata[6]
    DIRECTION OUTPUT ;
    USE SIGNAL ;
    ANTENNADIFFAREA 0.445500 ;
    PORT
      LAYER met2 ;
        RECT 212.610 0.000 212.890 4.000 ;
    END
  END m_wdata[6]
  PIN m_wdata[7]
    DIRECTION OUTPUT ;
    USE SIGNAL ;
    ANTENNADIFFAREA 0.445500 ;
    PORT
      LAYER met2 ;
        RECT 289.890 0.000 290.170 4.000 ;
    END
  END m_wdata[7]
  PIN m_wdata[8]
    DIRECTION OUTPUT ;
    USE SIGNAL ;
    ANTENNADIFFAREA 0.445500 ;
    PORT
      LAYER met2 ;
        RECT 299.550 0.000 299.830 4.000 ;
    END
  END m_wdata[8]
  PIN m_wdata[9]
    DIRECTION OUTPUT ;
    USE SIGNAL ;
    ANTENNADIFFAREA 0.445500 ;
    PORT
      LAYER met2 ;
        RECT 273.790 0.000 274.070 4.000 ;
    END
  END m_wdata[9]
  PIN m_write
    DIRECTION OUTPUT ;
    USE SIGNAL ;
    ANTENNADIFFAREA 0.445500 ;
    PORT
      LAYER met2 ;
        RECT 293.110 0.000 293.390 4.000 ;
    END
  END m_write
  PIN m_wstrb[0]
    DIRECTION OUTPUT ;
    USE SIGNAL ;
    PORT
      LAYER met2 ;
        RECT 183.630 496.000 183.910 500.000 ;
    END
  END m_wstrb[0]
  PIN m_wstrb[1]
    DIRECTION OUTPUT ;
    USE SIGNAL ;
    ANTENNADIFFAREA 0.445500 ;
    PORT
      LAYER met3 ;
        RECT 496.000 204.040 500.000 204.640 ;
    END
  END m_wstrb[1]
  PIN m_wstrb[2]
    DIRECTION OUTPUT ;
    USE SIGNAL ;
    ANTENNADIFFAREA 0.445500 ;
    PORT
      LAYER met3 ;
        RECT 496.000 210.840 500.000 211.440 ;
    END
  END m_wstrb[2]
  PIN m_wstrb[3]
    DIRECTION OUTPUT ;
    USE SIGNAL ;
    ANTENNADIFFAREA 0.445500 ;
    PORT
      LAYER met3 ;
        RECT 496.000 207.440 500.000 208.040 ;
    END
  END m_wstrb[3]
  PIN rst_n
    DIRECTION INPUT ;
    USE SIGNAL ;
    ANTENNAGATEAREA 0.159000 ;
    PORT
      LAYER met3 ;
        RECT 496.000 248.240 500.000 248.840 ;
    END
  END rst_n
  PIN ui_in[0]
    DIRECTION INPUT ;
    USE SIGNAL ;
    PORT
      LAYER met2 ;
        RECT 0.090 0.000 0.370 4.000 ;
    END
  END ui_in[0]
  PIN ui_in[1]
    DIRECTION INPUT ;
    USE SIGNAL ;
    PORT
      LAYER met2 ;
        RECT 3.310 0.000 3.590 4.000 ;
    END
  END ui_in[1]
  PIN ui_in[2]
    DIRECTION INPUT ;
    USE SIGNAL ;
    PORT
      LAYER met2 ;
        RECT 6.530 0.000 6.810 4.000 ;
    END
  END ui_in[2]
  PIN ui_in[3]
    DIRECTION INPUT ;
    USE SIGNAL ;
    PORT
      LAYER met2 ;
        RECT 9.750 0.000 10.030 4.000 ;
    END
  END ui_in[3]
  PIN ui_in[4]
    DIRECTION INPUT ;
    USE SIGNAL ;
    PORT
      LAYER met2 ;
        RECT 12.970 0.000 13.250 4.000 ;
    END
  END ui_in[4]
  PIN ui_in[5]
    DIRECTION INPUT ;
    USE SIGNAL ;
    PORT
      LAYER met2 ;
        RECT 16.190 0.000 16.470 4.000 ;
    END
  END ui_in[5]
  PIN ui_in[6]
    DIRECTION INPUT ;
    USE SIGNAL ;
    PORT
      LAYER met2 ;
        RECT 19.410 0.000 19.690 4.000 ;
    END
  END ui_in[6]
  PIN ui_in[7]
    DIRECTION INPUT ;
    USE SIGNAL ;
    PORT
      LAYER met2 ;
        RECT 22.630 0.000 22.910 4.000 ;
    END
  END ui_in[7]
  PIN uo_out[0]
    DIRECTION OUTPUT ;
    USE SIGNAL ;
    PORT
      LAYER met3 ;
        RECT 496.000 27.240 500.000 27.840 ;
    END
  END uo_out[0]
  PIN uo_out[1]
    DIRECTION OUTPUT ;
    USE SIGNAL ;
    PORT
      LAYER met2 ;
        RECT 425.130 496.000 425.410 500.000 ;
    END
  END uo_out[1]
  PIN uo_out[2]
    DIRECTION OUTPUT ;
    USE SIGNAL ;
    PORT
      LAYER met3 ;
        RECT 496.000 142.840 500.000 143.440 ;
    END
  END uo_out[2]
  PIN uo_out[3]
    DIRECTION OUTPUT ;
    USE SIGNAL ;
    PORT
      LAYER met2 ;
        RECT 238.370 0.000 238.650 4.000 ;
    END
  END uo_out[3]
  PIN uo_out[4]
    DIRECTION OUTPUT ;
    USE SIGNAL ;
    PORT
      LAYER met3 ;
        RECT 0.000 418.240 4.000 418.840 ;
    END
  END uo_out[4]
  PIN uo_out[5]
    DIRECTION OUTPUT ;
    USE SIGNAL ;
    PORT
      LAYER met2 ;
        RECT 83.810 0.000 84.090 4.000 ;
    END
  END uo_out[5]
  PIN uo_out[6]
    DIRECTION OUTPUT ;
    USE SIGNAL ;
    PORT
      LAYER met3 ;
        RECT 0.000 241.440 4.000 242.040 ;
    END
  END uo_out[6]
  PIN uo_out[7]
    DIRECTION OUTPUT ;
    USE SIGNAL ;
    PORT
      LAYER met2 ;
        RECT 367.170 0.000 367.450 4.000 ;
    END
  END uo_out[7]
  PIN user_interrupt
    DIRECTION OUTPUT ;
    USE SIGNAL ;
    ANTENNADIFFAREA 0.445500 ;
    PORT
      LAYER met3 ;
        RECT 496.000 241.440 500.000 242.040 ;
    END
  END user_interrupt
  PIN vccd1
    DIRECTION INOUT ;
    USE POWER ;
    PORT
      LAYER met4 ;
        RECT 21.040 10.640 22.640 487.120 ;
    END
    PORT
      LAYER met4 ;
        RECT 174.640 10.640 176.240 487.120 ;
    END
    PORT
      LAYER met4 ;
        RECT 328.240 10.640 329.840 487.120 ;
    END
    PORT
      LAYER met4 ;
        RECT 481.840 10.640 483.440 487.120 ;
    END
    PORT
      LAYER met5 ;
        RECT 5.280 26.730 494.280 28.330 ;
    END
    PORT
      LAYER met5 ;
        RECT 5.280 179.910 494.280 181.510 ;
    END
    PORT
      LAYER met5 ;
        RECT 5.280 333.090 494.280 334.690 ;
    END
  END vccd1
  PIN vssd1
    DIRECTION INOUT ;
    USE GROUND ;
    PORT
      LAYER met4 ;
        RECT 24.340 10.640 25.940 487.120 ;
    END
    PORT
      LAYER met4 ;
        RECT 177.940 10.640 179.540 487.120 ;
    END
    PORT
      LAYER met4 ;
        RECT 331.540 10.640 333.140 487.120 ;
    END
    PORT
      LAYER met4 ;
        RECT 485.140 10.640 486.740 487.120 ;
    END
    PORT
      LAYER met5 ;
        RECT 5.280 30.030 494.280 31.630 ;
    END
    PORT
      LAYER met5 ;
        RECT 5.280 183.210 494.280 184.810 ;
    END
    PORT
      LAYER met5 ;
        RECT 5.280 336.390 494.280 337.990 ;
    END
  END vssd1
  OBS
      LAYER nwell ;
        RECT 5.330 10.795 494.230 487.070 ;
      LAYER li1 ;
        RECT 5.520 10.795 494.040 486.965 ;
      LAYER met1 ;
        RECT 4.210 9.220 494.040 487.120 ;
      LAYER met2 ;
        RECT 4.230 495.720 164.030 496.810 ;
        RECT 164.870 495.720 167.250 496.810 ;
        RECT 168.090 495.720 170.470 496.810 ;
        RECT 171.310 495.720 173.690 496.810 ;
        RECT 174.530 495.720 176.910 496.810 ;
        RECT 177.750 495.720 180.130 496.810 ;
        RECT 180.970 495.720 183.350 496.810 ;
        RECT 184.190 495.720 186.570 496.810 ;
        RECT 187.410 495.720 189.790 496.810 ;
        RECT 190.630 495.720 193.010 496.810 ;
        RECT 193.850 495.720 196.230 496.810 ;
        RECT 197.070 495.720 199.450 496.810 ;
        RECT 200.290 495.720 202.670 496.810 ;
        RECT 203.510 495.720 205.890 496.810 ;
        RECT 206.730 495.720 209.110 496.810 ;
        RECT 209.950 495.720 212.330 496.810 ;
        RECT 213.170 495.720 215.550 496.810 ;
        RECT 216.390 495.720 218.770 496.810 ;
        RECT 219.610 495.720 221.990 496.810 ;
        RECT 222.830 495.720 225.210 496.810 ;
        RECT 226.050 495.720 228.430 496.810 ;
        RECT 229.270 495.720 231.650 496.810 ;
        RECT 232.490 495.720 234.870 496.810 ;
        RECT 235.710 495.720 238.090 496.810 ;
        RECT 238.930 495.720 241.310 496.810 ;
        RECT 242.150 495.720 244.530 496.810 ;
        RECT 245.370 495.720 247.750 496.810 ;
        RECT 248.590 495.720 250.970 496.810 ;
        RECT 251.810 495.720 254.190 496.810 ;
        RECT 255.030 495.720 257.410 496.810 ;
        RECT 258.250 495.720 260.630 496.810 ;
        RECT 261.470 495.720 263.850 496.810 ;
        RECT 264.690 495.720 267.070 496.810 ;
        RECT 267.910 495.720 270.290 496.810 ;
        RECT 271.130 495.720 273.510 496.810 ;
        RECT 274.350 495.720 276.730 496.810 ;
        RECT 277.570 495.720 279.950 496.810 ;
        RECT 280.790 495.720 283.170 496.810 ;
        RECT 284.010 495.720 286.390 496.810 ;
        RECT 287.230 495.720 289.610 496.810 ;
        RECT 290.450 495.720 292.830 496.810 ;
        RECT 293.670 495.720 296.050 496.810 ;
        RECT 296.890 495.720 299.270 496.810 ;
        RECT 300.110 495.720 302.490 496.810 ;
        RECT 303.330 495.720 305.710 496.810 ;
        RECT 306.550 495.720 308.930 496.810 ;
        RECT 309.770 495.720 315.370 496.810 ;
        RECT 316.210 495.720 318.590 496.810 ;
        RECT 319.430 495.720 321.810 496.810 ;
        RECT 322.650 495.720 325.030 496.810 ;
        RECT 325.870 495.720 424.850 496.810 ;
        RECT 425.690 495.720 492.570 496.810 ;
        RECT 4.230 4.280 492.570 495.720 ;
        RECT 4.230 3.670 6.250 4.280 ;
        RECT 7.090 3.670 9.470 4.280 ;
        RECT 10.310 3.670 12.690 4.280 ;
        RECT 13.530 3.670 15.910 4.280 ;
        RECT 16.750 3.670 19.130 4.280 ;
        RECT 19.970 3.670 22.350 4.280 ;
        RECT 23.190 3.670 83.530 4.280 ;
        RECT 84.370 3.670 93.190 4.280 ;
        RECT 94.030 3.670 154.370 4.280 ;
        RECT 155.210 3.670 157.590 4.280 ;
        RECT 158.430 3.670 160.810 4.280 ;
        RECT 161.650 3.670 164.030 4.280 ;
        RECT 164.870 3.670 167.250 4.280 ;
        RECT 168.090 3.670 170.470 4.280 ;
        RECT 171.310 3.670 173.690 4.280 ;
        RECT 174.530 3.670 176.910 4.280 ;
        RECT 177.750 3.670 180.130 4.280 ;
        RECT 180.970 3.670 183.350 4.280 ;
        RECT 184.190 3.670 186.570 4.280 ;
        RECT 187.410 3.670 189.790 4.280 ;
        RECT 190.630 3.670 193.010 4.280 ;
        RECT 193.850 3.670 196.230 4.280 ;
        RECT 197.070 3.670 199.450 4.280 ;
        RECT 200.290 3.670 202.670 4.280 ;
        RECT 203.510 3.670 205.890 4.280 ;
        RECT 206.730 3.670 209.110 4.280 ;
        RECT 209.950 3.670 212.330 4.280 ;
        RECT 213.170 3.670 215.550 4.280 ;
        RECT 216.390 3.670 218.770 4.280 ;
        RECT 219.610 3.670 221.990 4.280 ;
        RECT 222.830 3.670 225.210 4.280 ;
        RECT 226.050 3.670 228.430 4.280 ;
        RECT 229.270 3.670 231.650 4.280 ;
        RECT 232.490 3.670 234.870 4.280 ;
        RECT 235.710 3.670 238.090 4.280 ;
        RECT 238.930 3.670 241.310 4.280 ;
        RECT 242.150 3.670 244.530 4.280 ;
        RECT 245.370 3.670 247.750 4.280 ;
        RECT 248.590 3.670 250.970 4.280 ;
        RECT 251.810 3.670 254.190 4.280 ;
        RECT 255.030 3.670 257.410 4.280 ;
        RECT 258.250 3.670 260.630 4.280 ;
        RECT 261.470 3.670 263.850 4.280 ;
        RECT 264.690 3.670 267.070 4.280 ;
        RECT 267.910 3.670 270.290 4.280 ;
        RECT 271.130 3.670 273.510 4.280 ;
        RECT 274.350 3.670 276.730 4.280 ;
        RECT 277.570 3.670 279.950 4.280 ;
        RECT 280.790 3.670 283.170 4.280 ;
        RECT 284.010 3.670 286.390 4.280 ;
        RECT 287.230 3.670 289.610 4.280 ;
        RECT 290.450 3.670 292.830 4.280 ;
        RECT 293.670 3.670 296.050 4.280 ;
        RECT 296.890 3.670 299.270 4.280 ;
        RECT 300.110 3.670 302.490 4.280 ;
        RECT 303.330 3.670 305.710 4.280 ;
        RECT 306.550 3.670 308.930 4.280 ;
        RECT 309.770 3.670 312.150 4.280 ;
        RECT 312.990 3.670 315.370 4.280 ;
        RECT 316.210 3.670 318.590 4.280 ;
        RECT 319.430 3.670 321.810 4.280 ;
        RECT 322.650 3.670 325.030 4.280 ;
        RECT 325.870 3.670 328.250 4.280 ;
        RECT 329.090 3.670 331.470 4.280 ;
        RECT 332.310 3.670 334.690 4.280 ;
        RECT 335.530 3.670 337.910 4.280 ;
        RECT 338.750 3.670 341.130 4.280 ;
        RECT 341.970 3.670 344.350 4.280 ;
        RECT 345.190 3.670 347.570 4.280 ;
        RECT 348.410 3.670 350.790 4.280 ;
        RECT 351.630 3.670 354.010 4.280 ;
        RECT 354.850 3.670 357.230 4.280 ;
        RECT 358.070 3.670 360.450 4.280 ;
        RECT 361.290 3.670 363.670 4.280 ;
        RECT 364.510 3.670 366.890 4.280 ;
        RECT 367.730 3.670 370.110 4.280 ;
        RECT 370.950 3.670 373.330 4.280 ;
        RECT 374.170 3.670 376.550 4.280 ;
        RECT 377.390 3.670 379.770 4.280 ;
        RECT 380.610 3.670 382.990 4.280 ;
        RECT 383.830 3.670 386.210 4.280 ;
        RECT 387.050 3.670 389.430 4.280 ;
        RECT 390.270 3.670 492.570 4.280 ;
      LAYER met3 ;
        RECT 3.990 419.240 496.000 487.045 ;
        RECT 4.400 417.840 496.000 419.240 ;
        RECT 3.990 327.440 496.000 417.840 ;
        RECT 4.400 326.040 496.000 327.440 ;
        RECT 3.990 324.040 496.000 326.040 ;
        RECT 4.400 322.640 496.000 324.040 ;
        RECT 3.990 320.640 496.000 322.640 ;
        RECT 4.400 319.240 496.000 320.640 ;
        RECT 3.990 317.240 496.000 319.240 ;
        RECT 4.400 315.840 496.000 317.240 ;
        RECT 3.990 313.840 496.000 315.840 ;
        RECT 4.400 312.440 496.000 313.840 ;
        RECT 3.990 310.440 496.000 312.440 ;
        RECT 4.400 309.040 496.000 310.440 ;
        RECT 3.990 307.040 496.000 309.040 ;
        RECT 4.400 305.640 496.000 307.040 ;
        RECT 3.990 303.640 496.000 305.640 ;
        RECT 4.400 302.240 496.000 303.640 ;
        RECT 3.990 300.240 496.000 302.240 ;
        RECT 4.400 298.840 496.000 300.240 ;
        RECT 3.990 296.840 496.000 298.840 ;
        RECT 4.400 295.440 496.000 296.840 ;
        RECT 3.990 293.440 496.000 295.440 ;
        RECT 4.400 292.040 496.000 293.440 ;
        RECT 3.990 290.040 496.000 292.040 ;
        RECT 4.400 288.640 496.000 290.040 ;
        RECT 3.990 286.640 496.000 288.640 ;
        RECT 4.400 285.240 496.000 286.640 ;
        RECT 3.990 283.240 496.000 285.240 ;
        RECT 4.400 281.840 496.000 283.240 ;
        RECT 3.990 279.840 496.000 281.840 ;
        RECT 4.400 278.440 496.000 279.840 ;
        RECT 3.990 276.440 496.000 278.440 ;
        RECT 4.400 275.040 496.000 276.440 ;
        RECT 3.990 273.040 496.000 275.040 ;
        RECT 4.400 271.640 496.000 273.040 ;
        RECT 3.990 269.640 496.000 271.640 ;
        RECT 4.400 268.240 496.000 269.640 ;
        RECT 3.990 266.240 496.000 268.240 ;
        RECT 4.400 264.840 496.000 266.240 ;
        RECT 3.990 262.840 496.000 264.840 ;
        RECT 4.400 261.440 496.000 262.840 ;
        RECT 3.990 259.440 496.000 261.440 ;
        RECT 4.400 258.040 496.000 259.440 ;
        RECT 3.990 256.040 496.000 258.040 ;
        RECT 4.400 254.640 496.000 256.040 ;
        RECT 3.990 252.640 496.000 254.640 ;
        RECT 4.400 251.240 496.000 252.640 ;
        RECT 3.990 249.240 496.000 251.240 ;
        RECT 4.400 247.840 495.600 249.240 ;
        RECT 3.990 245.840 496.000 247.840 ;
        RECT 4.400 244.440 496.000 245.840 ;
        RECT 3.990 242.440 496.000 244.440 ;
        RECT 4.400 241.040 495.600 242.440 ;
        RECT 3.990 239.040 496.000 241.040 ;
        RECT 4.400 237.640 496.000 239.040 ;
        RECT 3.990 235.640 496.000 237.640 ;
        RECT 4.400 234.240 495.600 235.640 ;
        RECT 3.990 232.240 496.000 234.240 ;
        RECT 4.400 230.840 496.000 232.240 ;
        RECT 3.990 228.840 496.000 230.840 ;
        RECT 4.400 227.440 495.600 228.840 ;
        RECT 3.990 225.440 496.000 227.440 ;
        RECT 4.400 224.040 496.000 225.440 ;
        RECT 3.990 222.040 496.000 224.040 ;
        RECT 4.400 220.640 495.600 222.040 ;
        RECT 3.990 218.640 496.000 220.640 ;
        RECT 4.400 217.240 495.600 218.640 ;
        RECT 3.990 215.240 496.000 217.240 ;
        RECT 4.400 213.840 495.600 215.240 ;
        RECT 3.990 211.840 496.000 213.840 ;
        RECT 4.400 210.440 495.600 211.840 ;
        RECT 3.990 208.440 496.000 210.440 ;
        RECT 4.400 207.040 495.600 208.440 ;
        RECT 3.990 205.040 496.000 207.040 ;
        RECT 4.400 203.640 495.600 205.040 ;
        RECT 3.990 201.640 496.000 203.640 ;
        RECT 4.400 200.240 496.000 201.640 ;
        RECT 3.990 198.240 496.000 200.240 ;
        RECT 4.400 196.840 496.000 198.240 ;
        RECT 3.990 177.840 496.000 196.840 ;
        RECT 3.990 176.440 495.600 177.840 ;
        RECT 3.990 174.440 496.000 176.440 ;
        RECT 4.400 173.040 496.000 174.440 ;
        RECT 3.990 167.640 496.000 173.040 ;
        RECT 4.400 166.240 495.600 167.640 ;
        RECT 3.990 164.240 496.000 166.240 ;
        RECT 3.990 162.840 495.600 164.240 ;
        RECT 3.990 160.840 496.000 162.840 ;
        RECT 3.990 159.440 495.600 160.840 ;
        RECT 3.990 157.440 496.000 159.440 ;
        RECT 3.990 156.040 495.600 157.440 ;
        RECT 3.990 154.040 496.000 156.040 ;
        RECT 3.990 152.640 495.600 154.040 ;
        RECT 3.990 150.640 496.000 152.640 ;
        RECT 3.990 149.240 495.600 150.640 ;
        RECT 3.990 147.240 496.000 149.240 ;
        RECT 3.990 145.840 495.600 147.240 ;
        RECT 3.990 143.840 496.000 145.840 ;
        RECT 3.990 142.440 495.600 143.840 ;
        RECT 3.990 137.040 496.000 142.440 ;
        RECT 3.990 135.640 495.600 137.040 ;
        RECT 3.990 130.240 496.000 135.640 ;
        RECT 3.990 128.840 495.600 130.240 ;
        RECT 3.990 109.840 496.000 128.840 ;
        RECT 3.990 108.440 495.600 109.840 ;
        RECT 3.990 28.240 496.000 108.440 ;
        RECT 3.990 26.840 495.600 28.240 ;
        RECT 3.990 10.715 496.000 26.840 ;
      LAYER met4 ;
        RECT 111.615 13.095 174.240 483.985 ;
        RECT 176.640 13.095 177.540 483.985 ;
        RECT 179.940 13.095 327.840 483.985 ;
        RECT 330.240 13.095 331.140 483.985 ;
        RECT 333.540 13.095 370.465 483.985 ;
  END
END tqvp_dma
END LIBRARY

